VERSION 5.8 ;
BUSBITCHARS "[]" ;
DIVIDERCHAR "/" ;
UNITS
  DATABASE MICRONS 1000 ;
END UNITS

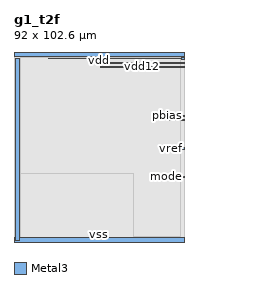
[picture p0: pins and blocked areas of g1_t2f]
MACRO g1_t2f
  CLASS BLOCK ;
  ORIGIN 0 0 ;
  FOREIGN g1_t2f 0 0 ;
  SIZE 92 BY 102.6 ;
  SYMMETRY X Y ;
  PIN vdd
    DIRECTION INOUT ;
    USE POWER ;
    PORT
      LAYER Metal3 ;
        RECT 0 100 92 102.6 ;
    END
  END vdd
  PIN vdd12
    DIRECTION INOUT ;
    USE POWER ;
    PORT
      LAYER Metal3 ;
        RECT 90.4 94.2 92 95 ;
    END
    PORT
      LAYER Metal3 ;
        RECT 46.62 94.35 92 94.85 ;
    END
  END vdd12
  PIN vss
    DIRECTION INOUT ;
    USE GROUND ;
    PORT
      LAYER Metal3 ;
        RECT 0 0 92 2.6 ;
    END
    PORT
      LAYER Metal3 ;
        RECT 0.6 0.6 3 99.2 ;
    END
  END vss
  PIN pbias
    DIRECTION INPUT ;
    USE SIGNAL ;
    PORT
      LAYER Metal3 ;
        RECT 90.4 67.7 92 68.5 ;
    END
    PORT
      LAYER Metal3 ;
        RECT 83.8 67.85 92 68.35 ;
    END
  END pbias
  PIN pcasc
    DIRECTION INPUT ;
    USE SIGNAL ;
    PORT
      LAYER Metal3 ;
        RECT 90.4 65.5 92 66.3 ;
    END
    PORT
      LAYER Metal3 ;
        RECT 83.8 65.65 92 66.15 ;
    END
  END pcasc
  PIN vref
    DIRECTION INPUT ;
    USE SIGNAL ;
    PORT
      LAYER Metal3 ;
        RECT 90.4 50.1 92 50.9 ;
    END
    PORT
      LAYER Metal3 ;
        RECT 83.8 50.25 92 50.75 ;
    END
  END vref
  PIN en
    DIRECTION INPUT ;
    USE SIGNAL ;
    PORT
      LAYER Metal3 ;
        RECT 90.4 98.7 92 99.5 ;
    END
    PORT
      LAYER Metal3 ;
        RECT 18.74 98.85 92 99.35 ;
    END
  END en
  PIN mode
    DIRECTION INPUT ;
    USE SIGNAL ;
    PORT
      LAYER Metal3 ;
        RECT 90.4 34.8 92 35.6 ;
    END
    PORT
      LAYER Metal3 ;
        RECT 83.8 34.95 92 35.45 ;
    END
  END mode
  PIN fout
    DIRECTION OUTPUT ;
    USE SIGNAL ;
    PORT
      LAYER Metal3 ;
        RECT 90.4 96.3 92 97.1 ;
    END
    PORT
      LAYER Metal3 ;
        RECT 44.87 96.45 92 96.95 ;
    END
  END fout
  OBS
    LAYER Metal1 ;
      RECT 0 0 92 102.6 ;
    LAYER Metal2 ;
      RECT 0 0 92 102.6 ;
    LAYER Metal3 ;
      RECT 3.4 3.0 89.9 99.6 ;
    LAYER Metal4 ;
      RECT 18.3 33.6 19.7 35 ;
    LAYER Metal4 ;
      RECT 48.3 33.6 49.7 35 ;
    LAYER Metal4 ;
      RECT 29.45 36.05 30.55 37.15 ;
    LAYER Metal5 ;
      RECT 4.15 3.35 63.85 33.05 ;
    LAYER Metal5 ;
      RECT 18.3 33.6 19.7 35 ;
    LAYER Metal5 ;
      RECT 48.3 33.6 49.7 35 ;
    LAYER Metal5 ;
      RECT 29.25 32.45 30.75 37.15 ;
    LAYER TopMetal1 ;
      RECT 3.5 2.7 64.5 37.04 ;
  END
END g1_t2f

END LIBRARY
